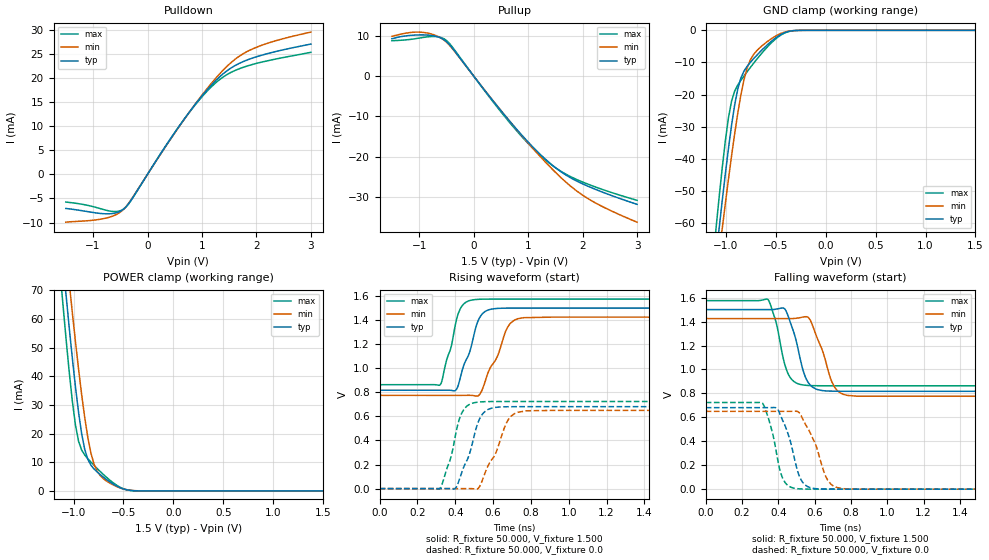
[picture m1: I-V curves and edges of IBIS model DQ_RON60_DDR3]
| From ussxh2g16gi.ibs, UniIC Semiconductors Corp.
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|   Model DQ_RON60_DDR3
[Model] DQ_RON60_DDR3
Model_type I/O
Vinl =  0.615V
Vinh =  0.885V
Vmeas =  0.750V
Rref =  50.000
Vref =  0.750V
C_comp   0.966pF   0.965pF   0.967pF
[Model Spec]
Vinh   0.885V   0.847V   0.922V
Vinl   0.615V   0.577V   0.652V
Vmeas   0.750V   0.712V   0.787V
Vref   0.750V   0.712V   0.787V
Rref   50.000   NA   NA
[Temperature Range]   25.000   95.000   -40.000
[Voltage Range]   1.500V   1.425V   1.575V
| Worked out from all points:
|   slope of the pulldown table from 0 to 0.225 V, typ, clamps not added: 56.5 ohm
|   slope of the pullup table from 0 to 0.225 V, typ, clamps not added: 57.4 ohm
|   GND clamp passes 1 mA (typ) near -0.43 V on its own axis
|   POWER clamp passes 1 mA (typ) near -0.52 V on its own axis
|   rising waveform, R_fixture 50.000, V_fixture 1.500: 20-80 % time 81.6ps typ, 103ps min, 66.8ps max; typ from 0.818 V to 1.5 V
|   rising waveform, R_fixture 50.000, V_fixture 0.0: 20-80 % time 84.5ps typ, 106ps min, 70.8ps max; typ from 0 V to 0.681 V
|   falling waveform, R_fixture 50.000, V_fixture 1.500: 20-80 % time 72ps typ, 86.9ps min, 63.1ps max; typ from 1.5 V to 0.818 V
|   falling waveform, R_fixture 50.000, V_fixture 0.0: 20-80 % time 76.5ps typ, 97.3ps min, 63.5ps max; typ from 0.681 V to 0 V
[Pulldown]
|Voltage   I(typ)   I(min)   I(max)
-1.5V     -7.077mA   -9.924mA   -5.748mA
-764mV    -8.187mA   -9.081mA   -7.434mA
-580mV    -7.998mA   -8.377mA   -7.72mA
-442mV    -7.252mA   -7.298mA   -7.217mA
-304mV    -5.41mA    -5.318mA   -5.451mA
662mV     11.26mA    11.21mA    11.24mA
984mV     16.05mA    16.18mA    15.87mA
1.26V     19.52mA    20.01mA    19.05mA
1.582V    22.39mA    23.63mA    21.41mA
1.858V    23.83mA    25.63mA    22.55mA
2.318V    25.36mA    27.58mA    23.82mA
3V        27.01mA    29.49mA    25.3mA
[Pullup]
|Voltage   I(typ)   I(min)   I(max)
-1.5V     9.205mA    9.811mA    8.722mA
-956mV    10.16mA    10.81mA    9.463mA
-726mV    9.917mA    10.17mA    9.772mA
-542mV    8.946mA    8.844mA    9.189mA
-404mV    7.122mA    6.979mA    7.402mA
700mV     -11.77mA   -11.79mA   -12.12mA
1.022V    -16.63mA   -16.89mA   -16.98mA
1.344V    -20.88mA   -21.65mA   -21.06mA
1.666V    -24.23mA   -25.9mA    -24.06mA
2.034V    -26.86mA   -29.75mA   -26.39mA
2.402V    -28.9mA    -32.53mA   -28.22mA
3V        -31.73mA   -36.14mA   -30.74mA
[GND_clamp]
|Voltage   I(typ)   I(min)   I(max)
-1.5V     -194.2mA   -188.5mA   -200.2mA
-1.097V   -70.36mA   -77.53mA   -61.46mA
-1.066V   -61.52mA   -69.48mA   -51.83mA
-1.035V   -52.91mA   -61.57mA   -42.69mA
-973mV    -36.75mA   -46.31mA   -27.23mA
-942mV    -29.54mA   -39.07mA   -22.03mA
-880mV    -18.29mA   -25.85mA   -17.02mA
-787mV    -11.24mA   -11.84mA   -12.91mA
-694mV    -7.909mA   -6.483mA   -9.178mA
-539mV    -3.3mA     -2.519mA   -3.76mA
-291mV    -42.28uA   -42.7uA    -38.22uA
1.5V      0A         0A         0A
[POWER_clamp]
|Voltage   I(typ)   I(min)   I(max)
-1.5V     238.9mA    243.4mA    236.4mA
-1.135V   91.01mA    105.1mA    76.96mA
-1.104V   79.29mA    94.04mA    64.51mA
-1.073V   67.84mA    83.12mA    52.53mA
-1.042V   56.75mA    72.44mA    41.28mA
-1.011V   46.15mA    62.05mA    31.18mA
-980mV    36.24mA    52.02mA    22.93mA
-887mV    14.41mA    25.48mA    12.52mA
-794mV    7.645mA    9.305mA    8.93mA
-670mV    3.99mA     3.471mA    4.77mA
-391mV    72.25uA    105.7uA    45.94uA
1.5V      0A         0A         0A
[Ramp]
| variable   typ   min   max
dV/dt_r   0.409/84.474p   0.390/0.106n   0.434/70.864p
dV/dt_f   0.409/71.683p   0.390/86.888p   0.427/62.993p
R_load = 50.000
[Rising Waveform]
R_fixture= 50.000
V_fixture= 1.500
V_fixture_min= 1.425
V_fixture_max= 1.575
|time   V(typ)   V(min)   V(max)
0s        817.6mV    774.9mV    863.6mV
318ps     817.5mV    774.9mV    859.9mV
405ps     821.8mV    774.9mV    1.396V
437ps     985.2mV    774.9mV    1.521V
493ps     1.239V     773.8mV    1.568V
520ps     1.392V     770.1mV    1.573V
558ps     1.472V     891.4mV    1.574V
677ps     1.5V       1.342V     1.575V
761ps     1.5V       1.42V      1.575V
3ns       1.5V       1.425V     1.575V
[Rising Waveform]
R_fixture= 50.000
V_fixture= 0.0
V_fixture_min= 0.0
V_fixture_max= 0.0
|time   V(typ)   V(min)   V(max)
0s        223nV      1.468uV    104.7nV
318ps     -36.75uV   3.619uV    -722.7uV
378ps     -789.6uV   2.971uV    268.1mV
405ps     11.05mV    -13.46uV   476mV
442ps     168.5mV    21.03uV    649.6mV
511ps     505.3mV    -4.537mV   716.9mV
571ps     655.8mV    182.9mV    723mV
671ps     680.2mV    547.7mV    723.8mV
729ps     680.9mV    634mV      723.8mV
3ns       681.1mV    650.1mV    723.8mV
[Falling Waveform]
R_fixture= 50.000
V_fixture= 1.500
V_fixture_min= 1.425
V_fixture_max= 1.575
|time   V(typ)   V(min)   V(max)
0s        1.5V       1.425V     1.575V
342ps     1.5V       1.425V     1.584V
386ps     1.503V     1.425V     1.403V
443ps     1.487V     1.425V     1.004V
497ps     1.248V     1.427V     888.3mV
532ps     1.014V     1.437V     871.3mV
576ps     868.3mV    1.412V     865.4mV
710ps     818.2mV    852mV      863.6mV
782ps     817.6mV    783.2mV    863.6mV
3ns       817.6mV    774.9mV    863.6mV
[Falling Waveform]
R_fixture= 50.000
V_fixture= 0.0
V_fixture_min= 0.0
V_fixture_max= 0.0
|time   V(typ)   V(min)   V(max)
0s        681.1mV    650.1mV    723.8mV
313ps     681mV      650mV      717.6mV
366ps     681.5mV    650mV      479.3mV
399ps     660.4mV    650mV      223.9mV
437ps     530.2mV    650mV      55.66mV
492ps     232.8mV    651.1mV    6.928mV
557ps     25.04mV    522mV      592.7uV
671ps     405.4uV    77.49mV    7.127uV
741ps     30.4uV     7.48mV     680.3nV
3ns       258.2nV    1.483uV    185.5nV
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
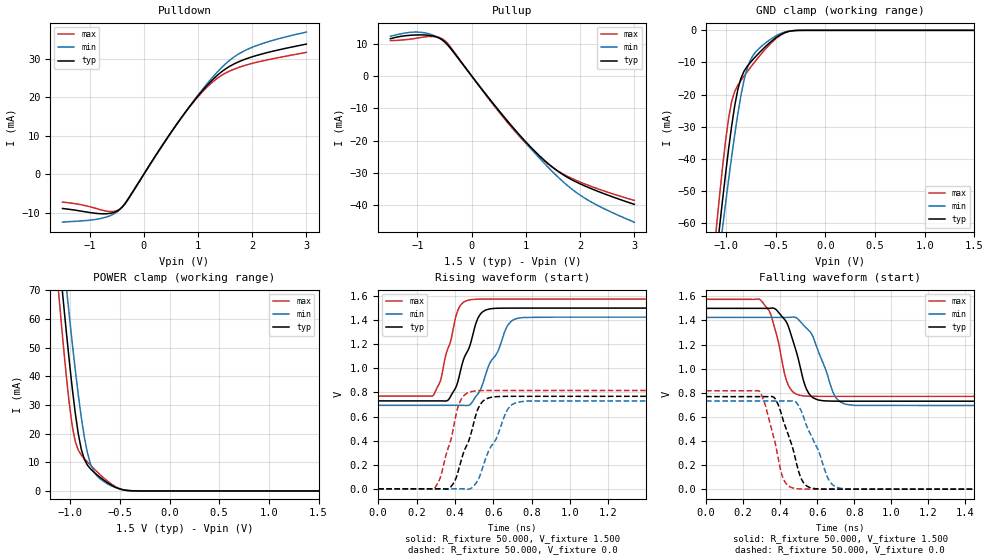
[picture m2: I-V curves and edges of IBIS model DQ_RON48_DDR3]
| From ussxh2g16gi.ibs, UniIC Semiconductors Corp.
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|   Model DQ_RON48_DDR3
[Model] DQ_RON48_DDR3
Model_type I/O
Vinl =  0.615V
Vinh =  0.885V
Vmeas =  0.750V
Rref =  50.000
Vref =  0.750V
C_comp   0.966pF   0.965pF   0.967pF
[Model Spec]
Vinh   0.885V   0.847V   0.922V
Vinl   0.615V   0.577V   0.652V
Vmeas   0.750V   0.712V   0.787V
Vref   0.750V   0.712V   0.787V
Rref   50.000   NA   NA
[Temperature Range]   25.000   95.000   -40.000
[Voltage Range]   1.500V   1.425V   1.575V
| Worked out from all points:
|   slope of the pulldown table from 0 to 0.225 V, typ, clamps not added: 45.2 ohm
|   slope of the pullup table from 0 to 0.225 V, typ, clamps not added: 45.9 ohm
|   GND clamp passes 1 mA (typ) near -0.43 V on its own axis
|   POWER clamp passes 1 mA (typ) near -0.52 V on its own axis
|   rising waveform, R_fixture 50.000, V_fixture 1.500: 20-80 % time 90.1ps typ, 117ps min, 72.2ps max; typ from 0.73 V to 1.5 V
|   rising waveform, R_fixture 50.000, V_fixture 0.0: 20-80 % time 91.1ps typ, 115ps min, 75.6ps max; typ from 0 V to 0.768 V
|   falling waveform, R_fixture 50.000, V_fixture 1.500: 20-80 % time 84.2ps typ, 104ps min, 72.3ps max; typ from 1.5 V to 0.73 V
|   falling waveform, R_fixture 50.000, V_fixture 0.0: 20-80 % time 90.3ps typ, 114ps min, 74.6ps max; typ from 0.768 V to 0 V
[Pulldown]
|Voltage   I(typ)   I(min)   I(max)
-1.5V     -8.855mA   -12.42mA   -7.198mA
-764mV    -10.24mA   -11.36mA   -9.305mA
-580mV    -10mA      -10.48mA   -9.66mA
-442mV    -9.069mA   -9.126mA   -9.029mA
-304mV    -6.766mA   -6.65mA    -6.819mA
662mV     14.08mA    14.02mA    14.06mA
984mV     20.07mA    20.24mA    19.85mA
1.26V     24.41mA    25.03mA    23.83mA
1.582V    28.01mA    29.56mA    26.79mA
1.858V    29.82mA    32.07mA    28.23mA
2.318V    31.73mA    34.51mA    29.82mA
3V        33.8mA     36.92mA    31.67mA
[Pullup]
|Voltage   I(typ)   I(min)   I(max)
-1.5V     11.52mA    12.28mA    10.93mA
-956mV    12.71mA    13.53mA    11.85mA
-726mV    12.41mA    12.72mA    12.23mA
-542mV    11.19mA    11.06mA    11.5mA
-404mV    8.909mA    8.73mA     9.263mA
700mV     -14.73mA   -14.75mA   -15.17mA
1.022V    -20.8mA    -21.12mA   -21.25mA
1.344V    -26.12mA   -27.08mA   -26.36mA
1.666V    -30.31mA   -32.4mA    -30.11mA
2.034V    -33.61mA   -37.23mA   -33.05mA
2.402V    -36.16mA   -40.71mA   -35.34mA
3V        -39.7mA    -45.23mA   -38.49mA
[GND_clamp]
|Voltage   I(typ)   I(min)   I(max)
-1.5V     -194.2mA   -188.5mA   -200.2mA
-1.097V   -70.36mA   -77.53mA   -61.46mA
-1.066V   -61.52mA   -69.48mA   -51.83mA
-1.035V   -52.91mA   -61.57mA   -42.69mA
-973mV    -36.75mA   -46.31mA   -27.23mA
-942mV    -29.54mA   -39.07mA   -22.03mA
-880mV    -18.29mA   -25.85mA   -17.02mA
-787mV    -11.24mA   -11.84mA   -12.91mA
-694mV    -7.909mA   -6.483mA   -9.178mA
-539mV    -3.3mA     -2.519mA   -3.76mA
-291mV    -42.28uA   -42.7uA    -38.22uA
1.5V      0A         0A         0A
[POWER_clamp]
|Voltage   I(typ)   I(min)   I(max)
-1.5V     238.9mA    243.4mA    236.4mA
-1.135V   91.01mA    105.1mA    76.96mA
-1.104V   79.29mA    94.04mA    64.51mA
-1.073V   67.84mA    83.12mA    52.53mA
-1.042V   56.75mA    72.44mA    41.28mA
-1.011V   46.15mA    62.05mA    31.18mA
-980mV    36.24mA    52.02mA    22.93mA
-887mV    14.41mA    25.48mA    12.52mA
-794mV    7.645mA    9.305mA    8.93mA
-670mV    3.99mA     3.471mA    4.77mA
-391mV    72.25uA    105.7uA    45.94uA
1.5V      0A         0A         0A
[Ramp]
| variable   typ   min   max
dV/dt_r   0.461/90.981p   0.439/0.115n   0.490/75.637p
dV/dt_f   0.462/83.868p   0.439/0.104n   0.483/72.416p
R_load = 50.000
[Rising Waveform]
R_fixture= 50.000
V_fixture= 1.500
V_fixture_min= 1.425
V_fixture_max= 1.575
|time   V(typ)   V(min)   V(max)
0s        729.8mV    693mV      769.8mV
290ps     729.8mV    693mV      781.2mV
324ps     729.8mV    693mV      894.4mV
370ps     747.4mV    693mV      1.189V
416ps     894.5mV    693.1mV    1.485V
478ps     1.189V     697.6mV    1.569V
542ps     1.466V     859.3mV    1.575V
669ps     1.5V       1.34V      1.575V
727ps     1.5V       1.416V     1.575V
3ns       1.5V       1.425V     1.575V
[Rising Waveform]
R_fixture= 50.000
V_fixture= 0.0
V_fixture_min= 0.0
V_fixture_max= 0.0
|time   V(typ)   V(min)   V(max)
0s        208.5nV    1.321uV    107.7nV
296ps     -18.19uV   4.319uV    9.245mV
328ps     122.6uV    5.59uV     115.8mV
398ps     60.93mV    18.37uV    556.4mV
436ps     255.5mV    130.7uV    752mV
493ps     515.5mV    15.18mV    809.4mV
552ps     735.6mV    213.1mV    815.8mV
673ps     767.5mV    654.6mV    816.5mV
722ps     767.9mV    718.1mV    816.5mV
3ns       767.9mV    731.2mV    816.5mV
[Falling Waveform]
R_fixture= 50.000
V_fixture= 1.500
V_fixture_min= 1.425
V_fixture_max= 1.575
|time   V(typ)   V(min)   V(max)
0s        1.5V       1.425V     1.575V
295ps     1.5V       1.425V     1.568V
352ps     1.502V     1.425V     1.435V
434ps     1.385V     1.425V     900.6mV
507ps     1.02V      1.394V     778.6mV
543ps     825.2mV    1.334V     772.1mV
575ps     760.7mV    1.271V     770.5mV
684ps     730.4mV    807.6mV    769.8mV
754ps     729.9mV    703.6mV    769.8mV
3ns       729.8mV    693mV      769.8mV
[Falling Waveform]
R_fixture= 50.000
V_fixture= 0.0
V_fixture_min= 0.0
V_fixture_max= 0.0
|time   V(typ)   V(min)   V(max)
0s        767.9mV    731.2mV    816.5mV
288ps     767.9mV    731.2mV    812.1mV
372ps     751.8mV    731.2mV    388.2mV
415ps     577.3mV    731.1mV    93.48mV
479ps     271.5mV    728.9mV    6.137mV
513ps     88.14mV    650.3mV    1.422mV
546ps     23.8mV     511.8mV    343.3uV
666ps     177.5uV    66.82mV    1.999uV
732ps     11.67uV    5.786mV    401.4nV
3ns       217.6nV    1.311uV    247.7nV
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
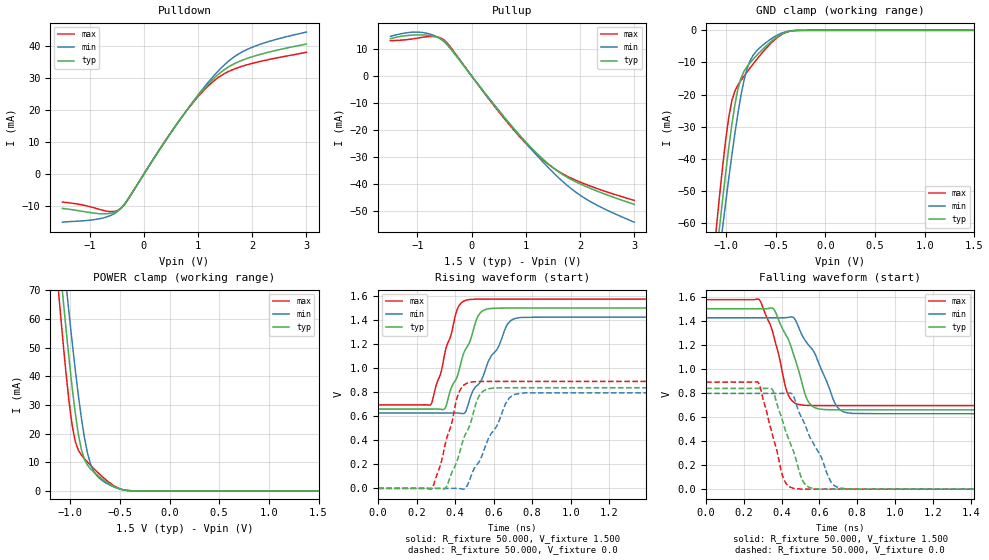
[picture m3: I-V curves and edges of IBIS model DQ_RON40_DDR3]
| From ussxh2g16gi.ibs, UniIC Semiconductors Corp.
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|   Model DQ_RON40_DDR3
[Model] DQ_RON40_DDR3
Model_type I/O
Vinl =  0.615V
Vinh =  0.885V
Vmeas =  0.750V
Rref =  50.000
Vref =  0.750V
C_comp   0.966pF   0.965pF   0.967pF
[Model Spec]
Vinh   0.885V   0.847V   0.922V
Vinl   0.615V   0.577V   0.652V
Vmeas   0.750V   0.712V   0.787V
Vref   0.750V   0.712V   0.787V
Rref   50.000   NA   NA
[Temperature Range]   25.000   95.000   -40.000
[Voltage Range]   1.500V   1.425V   1.575V
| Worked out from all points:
|   slope of the pulldown table from 0 to 0.225 V, typ, clamps not added: 37.7 ohm
|   slope of the pullup table from 0 to 0.225 V, typ, clamps not added: 38.3 ohm
|   GND clamp passes 1 mA (typ) near -0.43 V on its own axis
|   POWER clamp passes 1 mA (typ) near -0.52 V on its own axis
|   rising waveform, R_fixture 50.000, V_fixture 1.500: 20-80 % time 119ps typ, 160ps min, 91.2ps max; typ from 0.659 V to 1.5 V
|   rising waveform, R_fixture 50.000, V_fixture 0.0: 20-80 % time 108ps typ, 148ps min, 83.2ps max; typ from 0 V to 0.837 V
|   falling waveform, R_fixture 50.000, V_fixture 1.500: 20-80 % time 112ps typ, 151ps min, 87.1ps max; typ from 1.5 V to 0.659 V
|   falling waveform, R_fixture 50.000, V_fixture 0.0: 20-80 % time 107ps typ, 141ps min, 85.9ps max; typ from 0.837 V to 0 V
[Pulldown]
|Voltage   I(typ)   I(min)   I(max)
-1.5V     -10.61mA   -14.88mA   -8.617mA
-764mV    -12.27mA   -13.61mA   -11.14mA
-580mV    -11.99mA   -12.56mA   -11.57mA
-442mV    -10.87mA   -10.94mA   -10.82mA
-304mV    -8.107mA   -7.968mA   -8.167mA
662mV     16.87mA    16.8mA     16.84mA
984mV     24.04mA    24.25mA    23.77mA
1.26V     29.25mA    29.99mA    28.54mA
1.582V    33.55mA    35.4mA     32.08mA
1.858V    35.71mA    38.4mA     33.8mA
2.318V    38.01mA    41.32mA    35.7mA
3V        40.48mA    44.19mA    37.92mA
[Pullup]
|Voltage   I(typ)   I(min)   I(max)
-1.5V     13.8mA     14.7mA     13.07mA
-956mV    15.23mA    16.21mA    14.19mA
-726mV    14.86mA    15.24mA    14.65mA
-542mV    13.41mA    13.25mA    13.77mA
-404mV    10.67mA    10.46mA    11.09mA
700mV     -17.64mA   -17.67mA   -18.15mA
1.022V    -24.91mA   -25.3mA    -25.43mA
1.344V    -31.28mA   -32.43mA   -31.54mA
1.666V    -36.29mA   -38.79mA   -36.03mA
2.034V    -40.23mA   -44.56mA   -39.53mA
2.402V    -43.28mA   -48.71mA   -42.27mA
3V        -47.51mA   -54.1mA    -46.03mA
[GND_clamp]
|Voltage   I(typ)   I(min)   I(max)
-1.5V     -194.2mA   -188.5mA   -200.2mA
-1.097V   -70.36mA   -77.53mA   -61.46mA
-1.066V   -61.52mA   -69.48mA   -51.83mA
-1.035V   -52.91mA   -61.57mA   -42.69mA
-973mV    -36.75mA   -46.31mA   -27.23mA
-942mV    -29.54mA   -39.07mA   -22.03mA
-880mV    -18.29mA   -25.85mA   -17.02mA
-787mV    -11.24mA   -11.84mA   -12.91mA
-694mV    -7.909mA   -6.483mA   -9.178mA
-539mV    -3.3mA     -2.519mA   -3.76mA
-291mV    -42.28uA   -42.7uA    -38.22uA
1.5V      0A         0A         0A
[POWER_clamp]
|Voltage   I(typ)   I(min)   I(max)
-1.5V     238.9mA    243.4mA    236.4mA
-1.135V   91.01mA    105.1mA    76.96mA
-1.104V   79.29mA    94.04mA    64.51mA
-1.073V   67.84mA    83.12mA    52.53mA
-1.042V   56.75mA    72.44mA    41.28mA
-1.011V   46.15mA    62.05mA    31.18mA
-980mV    36.24mA    52.02mA    22.93mA
-887mV    14.41mA    25.48mA    12.52mA
-794mV    7.645mA    9.305mA    8.93mA
-670mV    3.99mA     3.471mA    4.77mA
-391mV    72.25uA    105.7uA    45.94uA
1.5V      0A         0A         0A
[Ramp]
| variable   typ   min   max
dV/dt_r   0.502/0.108n   0.478/0.148n   0.534/83.194p
dV/dt_f   0.504/0.112n   0.479/0.151n   0.528/86.940p
R_load = 50.000
[Rising Waveform]
R_fixture= 50.000
V_fixture= 1.500
V_fixture_min= 1.425
V_fixture_max= 1.575
|time   V(typ)   V(min)   V(max)
0s        659.5mV    627.1mV    694.9mV
276ps     659.4mV    627.1mV    702.7mV
349ps     671.3mV    627.1mV    1.144V
415ps     951.4mV    626.9mV    1.504V
451ps     1.149V     629.5mV    1.562V
468ps     1.192V     698.3mV    1.569V
538ps     1.472V     905.8mV    1.575V
666ps     1.5V       1.349V     1.575V
716ps     1.5V       1.416V     1.575V
3ns       1.5V       1.425V     1.575V
[Rising Waveform]
R_fixture= 50.000
V_fixture= 0.0
V_fixture_min= 0.0
V_fixture_max= 0.0
|time   V(typ)   V(min)   V(max)
0s        197.4nV    1.203uV    110.9nV
278ps     -66.61uV   3.295uV    -1.742mV
353ps     9.699mV    -49.68uV   398.3mV
422ps     291.8mV    -941.6uV   807.3mV
477ps     529.5mV    78.62mV    882mV
516ps     741.7mV    202.7mV    888.3mV
543ps     805.1mV    287.8mV    889.4mV
669ps     837.3mV    725.3mV    889.9mV
712ps     837.4mV    783.4mV    889.9mV
3ns       837.4mV    796.3mV    889.9mV
[Falling Waveform]
R_fixture= 50.000
V_fixture= 1.500
V_fixture_min= 1.425
V_fixture_max= 1.575
|time   V(typ)   V(min)   V(max)
0s        1.5V       1.425V     1.575V
281ps     1.5V       1.425V     1.576V
363ps     1.485V     1.425V     1.242V
430ps     1.262V     1.427V     801.3mV
466ps     1.105V     1.421V     719.9mV
499ps     934.8mV    1.31V      701.3mV
561ps     691mV      1.165V     695.4mV
679ps     659.7mV    722.9mV    694.9mV
746ps     659.5mV    635.2mV    694.9mV
3ns       659.5mV    627.1mV    694.9mV
[Falling Waveform]
R_fixture= 50.000
V_fixture= 0.0
V_fixture_min= 0.0
V_fixture_max= 0.0
|time   V(typ)   V(min)   V(max)
0s        837.4mV    796.3mV    889.9mV
274ps     837.4mV    796.3mV    890mV
352ps     823.8mV    796.3mV    445.5mV
414ps     518mV      796.2mV    72.23mV
467ps     295mV      757.2mV    5.888mV
500ps     112.7mV    610.4mV    1.231mV
532ps     28.36mV    500.3mV    280.8uV
662ps     87.94uV    58.13mV    776.6nV
701ps     15.26uV    12.07mV    330.4nV
3ns       226.3nV    1.164uV    156.2nV
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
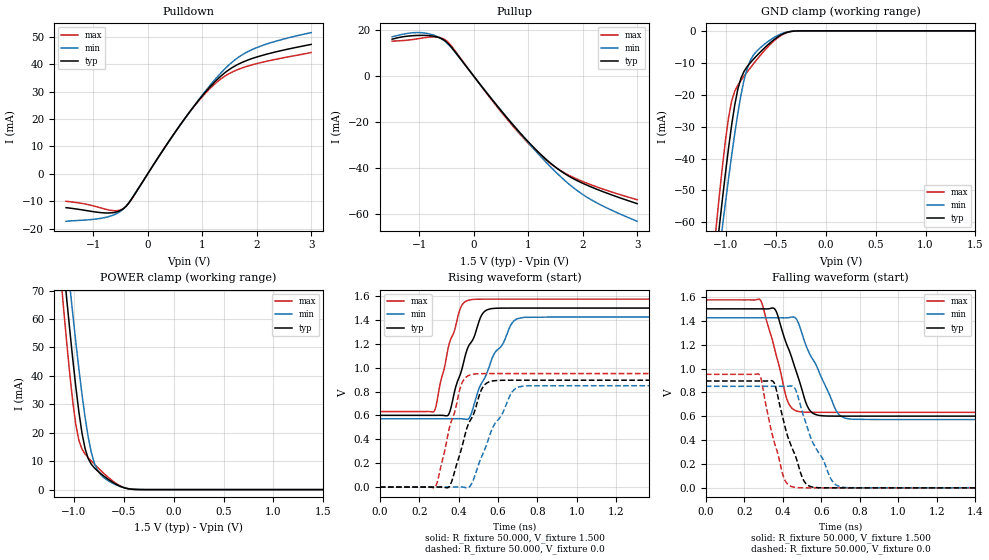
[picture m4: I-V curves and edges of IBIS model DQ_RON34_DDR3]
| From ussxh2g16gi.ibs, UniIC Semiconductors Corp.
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|   Model DQ_RON34_DDR3
[Model] DQ_RON34_DDR3
Model_type I/O
Vinl =  0.615V
Vinh =  0.885V
Vmeas =  0.750V
Rref =  50.000
Vref =  0.750V
C_comp   0.966pF   0.965pF   0.967pF
[Model Spec]
Vinh   0.885V   0.847V   0.922V
Vinl   0.615V   0.577V   0.652V
Vmeas   0.750V   0.712V   0.787V
Vref   0.750V   0.712V   0.787V
Rref   50.000   NA   NA
[Temperature Range]   25.000   95.000   -40.000
[Voltage Range]   1.500V   1.425V   1.575V
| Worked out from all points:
|   slope of the pulldown table from 0 to 0.225 V, typ, clamps not added: 32.3 ohm
|   slope of the pullup table from 0 to 0.225 V, typ, clamps not added: 32.8 ohm
|   GND clamp passes 1 mA (typ) near -0.43 V on its own axis
|   POWER clamp passes 1 mA (typ) near -0.52 V on its own axis
|   rising waveform, R_fixture 50.000, V_fixture 1.500: 20-80 % time 114ps typ, 151ps min, 89.1ps max; typ from 0.601 V to 1.5 V
|   rising waveform, R_fixture 50.000, V_fixture 0.0: 20-80 % time 108ps typ, 142ps min, 85.1ps max; typ from 0 V to 0.896 V
|   falling waveform, R_fixture 50.000, V_fixture 1.500: 20-80 % time 111ps typ, 145ps min, 90.4ps max; typ from 1.5 V to 0.601 V
|   falling waveform, R_fixture 50.000, V_fixture 0.0: 20-80 % time 102ps typ, 132ps min, 83.7ps max; typ from 0.896 V to 0 V
[Pulldown]
|Voltage   I(typ)   I(min)   I(max)
-1.5V     -12.39mA   -17.36mA   -10.06mA
-764mV    -14.32mA   -15.88mA   -13.01mA
-580mV    -13.99mA   -14.65mA   -13.51mA
-442mV    -12.68mA   -12.76mA   -12.62mA
-304mV    -9.452mA   -9.291mA   -9.524mA
662mV     19.67mA    19.59mA    19.64mA
984mV     28.04mA    28.27mA    27.73mA
1.26V     34.11mA    34.97mA    33.29mA
1.582V    39.13mA    41.28mA    37.42mA
1.858V    41.65mA    44.78mA    39.43mA
2.318V    44.33mA    48.19mA    41.64mA
3V        47.22mA    51.54mA    44.24mA
[Pullup]
|Voltage   I(typ)   I(min)   I(max)
-1.5V     16.11mA    17.15mA    15.27mA
-956mV    17.77mA    18.93mA    16.57mA
-726mV    17.35mA    17.79mA    17.1mA
-542mV    15.64mA    15.46mA    16.07mA
-404mV    12.45mA    12.2mA     12.94mA
700mV     -20.57mA   -20.61mA   -21.19mA
1.022V    -29.06mA   -29.51mA   -29.68mA
1.344V    -36.49mA   -37.83mA   -36.81mA
1.666V    -42.33mA   -45.25mA   -42.06mA
2.034V    -46.94mA   -51.98mA   -46.14mA
2.402V    -50.49mA   -56.83mA   -49.34mA
3V        -55.43mA   -63.11mA   -53.74mA
[GND_clamp]
|Voltage   I(typ)   I(min)   I(max)
-1.5V     -194.2mA   -188.5mA   -200.2mA
-1.097V   -70.36mA   -77.53mA   -61.46mA
-1.066V   -61.52mA   -69.48mA   -51.83mA
-1.035V   -52.91mA   -61.57mA   -42.69mA
-973mV    -36.75mA   -46.31mA   -27.23mA
-942mV    -29.54mA   -39.07mA   -22.03mA
-880mV    -18.29mA   -25.85mA   -17.02mA
-787mV    -11.24mA   -11.84mA   -12.91mA
-694mV    -7.909mA   -6.483mA   -9.178mA
-539mV    -3.3mA     -2.519mA   -3.76mA
-291mV    -42.28uA   -42.7uA    -38.22uA
1.5V      0A         0A         0A
[POWER_clamp]
|Voltage   I(typ)   I(min)   I(max)
-1.5V     238.9mA    243.4mA    236.4mA
-1.135V   91.01mA    105.1mA    76.96mA
-1.104V   79.29mA    94.04mA    64.51mA
-1.073V   67.84mA    83.12mA    52.53mA
-1.042V   56.75mA    72.44mA    41.28mA
-1.011V   46.15mA    62.05mA    31.18mA
-980mV    36.24mA    52.02mA    22.93mA
-887mV    14.41mA    25.48mA    12.52mA
-794mV    7.645mA    9.305mA    8.93mA
-670mV    3.99mA     3.471mA    4.77mA
-391mV    72.25uA    105.7uA    45.94uA
1.5V      0A         0A         0A
[Ramp]
| variable   typ   min   max
dV/dt_r   0.537/0.108n   0.510/0.142n   0.571/85.190p
dV/dt_f   0.539/0.111n   0.512/0.145n   0.565/90.271p
R_load = 50.000
[Rising Waveform]
R_fixture= 50.000
V_fixture= 1.500
V_fixture_min= 1.425
V_fixture_max= 1.575
|time   V(typ)   V(min)   V(max)
0s        601.1mV    572.4mV    632.7mV
276ps     601mV      572.5mV    635.5mV
352ps     617.7mV    572.4mV    1.201V
411ps     957.8mV    572.7mV    1.507V
455ps     1.195V     580mV      1.568V
535ps     1.476V     923.5mV    1.575V
573ps     1.496V     1.093V     1.575V
672ps     1.5V       1.378V     1.575V
731ps     1.5V       1.422V     1.575V
3ns       1.5V       1.425V     1.575V
[Rising Waveform]
R_fixture= 50.000
V_fixture= 0.0
V_fixture_min= 0.0
V_fixture_max= 0.0
|time   V(typ)   V(min)   V(max)
0s        187.9nV    1.105uV    113.1nV
281ps     -80.66uV   3.744uV    278uV
359ps     23.7mV     -66.36uV   534.3mV
416ps     332.9mV    210uV      868.9mV
473ps     601mV      54.4mV     945.8mV
536ps     863.6mV    330.4mV    951.1mV
572ps     889.3mV    497.5mV    951.3mV
667ps     895.5mV    787.1mV    951.4mV
719ps     895.6mV    844.2mV    951.4mV
3ns       895.6mV    850.7mV    951.4mV
[Falling Waveform]
R_fixture= 50.000
V_fixture= 1.500
V_fixture_min= 1.425
V_fixture_max= 1.575
|time   V(typ)   V(min)   V(max)
0s        1.5V       1.425V     1.575V
283ps     1.5V       1.425V     1.575V
365ps     1.482V     1.425V     1.117V
424ps     1.187V     1.425V     730.9mV
482ps     916.2mV    1.379V     639.9mV
526ps     690mV      1.172V     633.7mV
552ps     630.6mV    1.087V     633mV
678ps     601.2mV    645.3mV    632.7mV
741ps     601.1mV    578.3mV    632.7mV
3ns       601.1mV    572.4mV    632.7mV
[Falling Waveform]
R_fixture= 50.000
V_fixture= 0.0
V_fixture_min= 0.0
V_fixture_max= 0.0
|time   V(typ)   V(min)   V(max)
0s        895.6mV    850.7mV    951.4mV
280ps     895.5mV    850.7mV    945.4mV
357ps     873.1mV    850.7mV    375.7mV
409ps     529.1mV    850.4mV    71.39mV
457ps     301.7mV    847.9mV    6.079mV
501ps     87.93mV    639mV      607.7uV
530ps     22.28mV    493.9mV    131.1uV
654ps     57.75uV    63.91mV    525.9nV
697ps     7.75uV     9.89mV     286.6nV
3ns       165.2nV    1.074uV    89.97nV
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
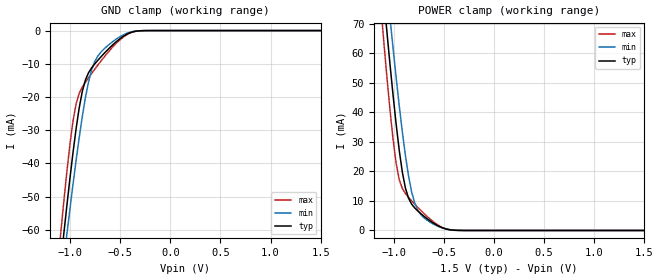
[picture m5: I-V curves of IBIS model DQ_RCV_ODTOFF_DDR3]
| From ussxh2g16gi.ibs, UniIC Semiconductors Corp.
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|   Model DQ_RCV_ODTOFF_DDR3
[Model] DQ_RCV_ODTOFF_DDR3
Model_type Input
Vinl =  0.615V
Vinh =  0.885V
C_comp   0.966pF   0.965pF   0.967pF
[Model Spec]
Vinh   0.885V   0.847V   0.922V
Vinl   0.615V   0.577V   0.652V
[Temperature Range]   25.000   95.000   -40.000
[Voltage Range]   1.500V   1.425V   1.575V
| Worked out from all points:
|   GND clamp passes 1 mA (typ) near -0.43 V on its own axis
|   POWER clamp passes 1 mA (typ) near -0.52 V on its own axis
[GND_clamp]
|Voltage   I(typ)   I(min)   I(max)
-1.5V     -194.2mA   -188.5mA   -200.2mA
-1.097V   -70.36mA   -77.53mA   -61.46mA
-1.066V   -61.52mA   -69.48mA   -51.83mA
-1.035V   -52.91mA   -61.57mA   -42.69mA
-973mV    -36.75mA   -46.31mA   -27.23mA
-942mV    -29.54mA   -39.07mA   -22.03mA
-880mV    -18.29mA   -25.85mA   -17.02mA
-787mV    -11.24mA   -11.84mA   -12.91mA
-694mV    -7.909mA   -6.483mA   -9.178mA
-539mV    -3.3mA     -2.519mA   -3.76mA
-291mV    -42.28uA   -42.7uA    -38.22uA
1.5V      0A         0A         0A
[POWER_clamp]
|Voltage   I(typ)   I(min)   I(max)
-1.5V     238.9mA    243.4mA    236.4mA
-1.135V   91.01mA    105.1mA    76.96mA
-1.104V   79.29mA    94.04mA    64.51mA
-1.073V   67.84mA    83.12mA    52.53mA
-1.042V   56.75mA    72.44mA    41.28mA
-1.011V   46.15mA    62.05mA    31.18mA
-980mV    36.24mA    52.02mA    22.93mA
-887mV    14.41mA    25.48mA    12.52mA
-794mV    7.645mA    9.305mA    8.93mA
-670mV    3.99mA     3.471mA    4.77mA
-391mV    72.25uA    105.7uA    45.94uA
1.5V      0A         0A         0A
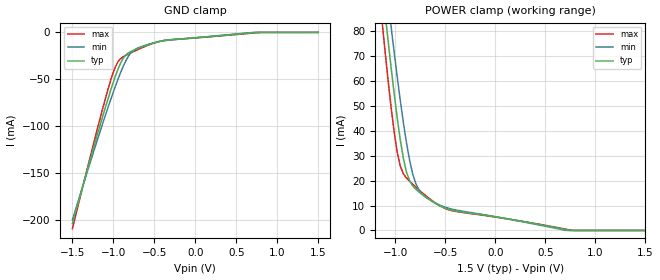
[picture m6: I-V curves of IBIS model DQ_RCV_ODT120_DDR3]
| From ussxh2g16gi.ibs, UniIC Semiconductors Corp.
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|   Model DQ_RCV_ODT120_DDR3
[Model] DQ_RCV_ODT120_DDR3
Model_type Input
Vinl =  0.615V
Vinh =  0.885V
C_comp   0.966pF   0.965pF   0.967pF
[Model Spec]
Vinh   0.885V   0.847V   0.922V
Vinl   0.615V   0.577V   0.652V
[Temperature Range]   25.000   95.000   -40.000
[Voltage Range]   1.500V   1.425V   1.575V
[GND_clamp]
|Voltage   I(typ)   I(min)   I(max)
-1.5V     -204mA     -200mA     -209.5mA
-1.252V   -126.2mA   -130.3mA   -122.2mA
-1.066V   -70.97mA   -80.25mA   -60.88mA
-973mV    -46.13mA   -56.89mA   -36.24mA
-911mV    -32.58mA   -42.66mA   -27.9mA
-849mV    -24.13mA   -30.5mA    -24.53mA
-818mV    -21.94mA   -25.7mA    -23.17mA
-756mV    -19.19mA   -19.43mA   -20.57mA
-663mV    -15.91mA   -15.34mA   -16.87mA
-446mV    -9.729mA   -9.883mA   -9.903mA
701mV     -368.9uA   -91.38uA   -759.9uA
1.5V      0A         0A         0A
[POWER_clamp]
|Voltage   I(typ)   I(min)   I(max)
-1.5V     248mA      253.3mA    245.1mA
-1.135V   100.1mA    115mA      85.49mA
-1.104V   88.4mA     103.9mA    73.03mA
-1.073V   76.94mA    92.95mA    61.05mA
-1.042V   65.83mA    82.25mA    49.8mA
-980mV    45.29mA    61.77mA    31.45mA
-887mV    23.4mA     35.12mA    21.04mA
-794mV    16.54mA    18.8mA     17.43mA
-670mV    12.71mA    12.7mA     13.18mA
-422mV    8.08mA     8.46mA     7.859mA
694mV     446.4uA    150.6uA    608.5uA
1.5V      0A         0A         0A
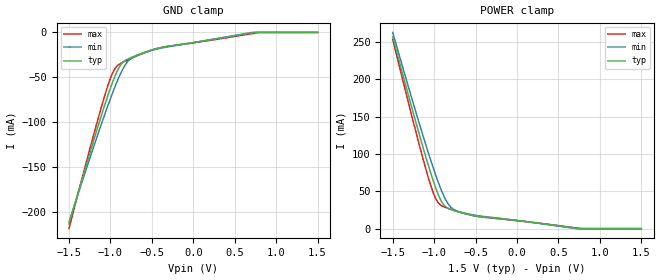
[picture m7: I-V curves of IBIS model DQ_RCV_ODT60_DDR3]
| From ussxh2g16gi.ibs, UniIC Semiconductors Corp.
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|   Model DQ_RCV_ODT60_DDR3
[Model] DQ_RCV_ODT60_DDR3
Model_type Input
Vinl =  0.615V
Vinh =  0.885V
C_comp   0.966pF   0.965pF   0.967pF
[Model Spec]
Vinh   0.885V   0.847V   0.922V
Vinl   0.615V   0.577V   0.652V
[Temperature Range]   25.000   95.000   -40.000
[Voltage Range]   1.500V   1.425V   1.575V
[GND_clamp]
|Voltage   I(typ)   I(min)   I(max)
-1.5V     -213.6mA   -211.3mA   -218.6mA
-1.221V   -126.2mA   -132.6mA   -120.5mA
-1.066V   -80.29mA   -90.85mA   -69.73mA
-973mV    -55.38mA   -67.32mA   -45.06mA
-911mV    -41.77mA   -52.96mA   -36.7mA
-849mV    -33.26mA   -40.67mA   -33.31mA
-756mV    -28.21mA   -29.37mA   -29.32mA
-632mV    -23.73mA   -23.99mA   -24.36mA
-415mV    -17.36mA   -18.03mA   -17.47mA
701mV     -718.2uA   -167.7uA   -1.484mA
825mV     0A         0A         0A
1.5V      0A         0A         0A
[POWER_clamp]
|Voltage   I(typ)   I(min)   I(max)
-1.5V     257mA      263mA      253.6mA
-1.228V   145.5mA    159mA      133mA
-1.073V   85.93mA    102.7mA    69.44mA
-1.011V   64.18mA    81.49mA    48.09mA
-980mV    54.24mA    71.4mA     39.83mA
-918mV    37.81mA    52.79mA    31.15mA
-856mV    28.78mA    37.65mA    28.12mA
-794mV    25.34mA    28.18mA    25.79mA
-732mV    23.23mA    23.97mA    23.58mA
-577mV    18.83mA    19.46mA    18.64mA
725mV     426.2uA    0A         767.9uA
1.5V      0A         0A         0A
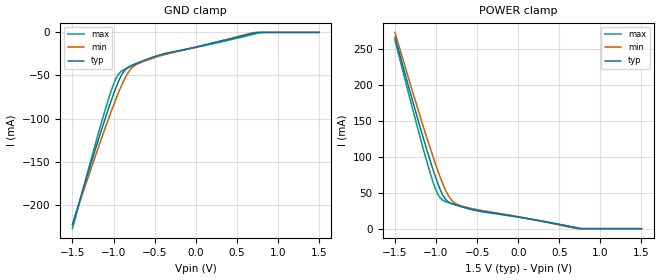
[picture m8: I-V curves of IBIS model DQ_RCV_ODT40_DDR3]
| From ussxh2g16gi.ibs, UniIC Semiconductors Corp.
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|   Model DQ_RCV_ODT40_DDR3
[Model] DQ_RCV_ODT40_DDR3
Model_type Input
Vinl =  0.615V
Vinh =  0.885V
C_comp   0.966pF   0.965pF   0.967pF
[Model Spec]
Vinh   0.885V   0.847V   0.922V
Vinl   0.615V   0.577V   0.652V
[Temperature Range]   25.000   95.000   -40.000
[Voltage Range]   1.500V   1.425V   1.575V
[GND_clamp]
|Voltage   I(typ)   I(min)   I(max)
-1.5V     -223.3mA   -222.7mA   -227.9mA
-1.221V   -135.7mA   -143.6mA   -129.6mA
-1.066V   -89.68mA   -101.5mA   -78.73mA
-973mV    -64.69mA   -77.83mA   -54.02mA
-911mV    -51.03mA   -63.34mA   -45.65mA
-849mV    -42.46mA   -50.92mA   -42.23mA
-756mV    -37.3mA    -39.39mA   -38.2mA
-663mV    -33.76mA   -34.78mA   -34.38mA
-415mV    -25.64mA   -26.75mA   -25.78mA
701mV     -1.089mA   -264.2uA   -2.245mA
825mV     0A         0A         0A
1.5V      0A         0A         0A
[POWER_clamp]
|Voltage   I(typ)   I(min)   I(max)
-1.5V     266.1mA    272.8mA    262.2mA
-1.228V   154.6mA    168.8mA    141.5mA
-1.073V   94.97mA    112.4mA    77.9mA
-1.011V   73.19mA    91.19mA    56.55mA
-980mV    63.23mA    81.08mA    48.3mA
-918mV    46.77mA    62.4mA     39.62mA
-856mV    37.69mA    47.17mA    36.58mA
-794mV    34.18mA    37.6mA     34.24mA
-732mV    31.99mA    33.26mA    31.99mA
-577mV    27.3mA     28.33mA    26.86mA
725mV     626.6uA    0A         1.132mA
1.5V      0A         0A         0A
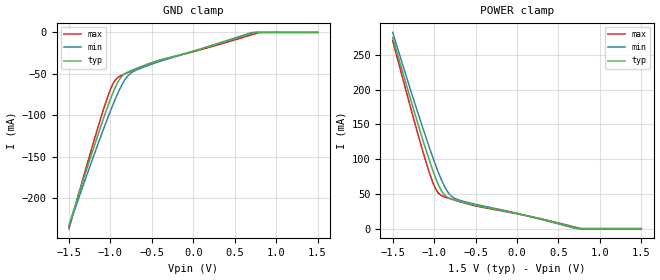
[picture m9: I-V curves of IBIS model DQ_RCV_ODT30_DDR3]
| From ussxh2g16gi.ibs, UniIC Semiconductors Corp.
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|   Model DQ_RCV_ODT30_DDR3
[Model] DQ_RCV_ODT30_DDR3
Model_type Input
Vinl =  0.615V
Vinh =  0.885V
C_comp   0.966pF   0.965pF   0.967pF
[Model Spec]
Vinh   0.885V   0.847V   0.922V
Vinl   0.615V   0.577V   0.652V
[Temperature Range]   25.000   95.000   -40.000
[Voltage Range]   1.500V   1.425V   1.575V
[GND_clamp]
|Voltage   I(typ)   I(min)   I(max)
-1.5V     -233mA     -234.1mA   -237mA
-1.221V   -145.1mA   -154.5mA   -138.6mA
-1.066V   -99.03mA   -112.2mA   -87.62mA
-973mV    -73.97mA   -88.29mA   -62.88mA
-911mV    -60.25mA   -73.68mA   -54.48mA
-818mV    -49.33mA   -56.09mA   -49.67mA
-756mV    -46.36mA   -49.36mA   -46.99mA
-694mV    -43.88mA   -45.82mA   -44.38mA
-415mV    -33.89mA   -35.43mA   -34.02mA
701mV     -1.444mA   -345.1uA   -2.979mA
825mV     0A         0A         0A
1.5V      0A         0A         0A
[POWER_clamp]
|Voltage   I(typ)   I(min)   I(max)
-1.5V     275.1mA    282.5mA    270.6mA
-1.228V   163.7mA    178.5mA    149.9mA
-1.073V   104mA      122.1mA    86.29mA
-1.011V   82.16mA    100.9mA    64.95mA
-980mV    72.19mA    90.72mA    56.69mA
-918mV    55.68mA    71.97mA    48.01mA
-856mV    46.55mA    56.66mA    44.97mA
-794mV    42.99mA    46.98mA    42.62mA
-732mV    40.72mA    42.52mA    40.34mA
-577mV    35.74mA    37.18mA    35.03mA
725mV     840.7uA    0A         1.516mA
1.5V      0A         0A         0A
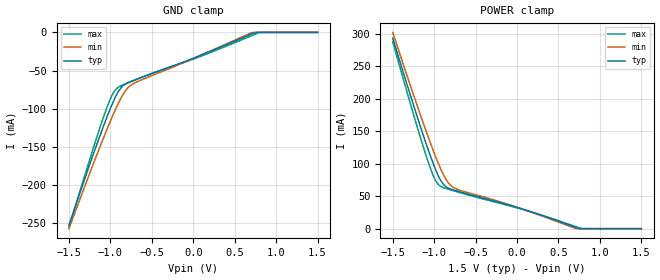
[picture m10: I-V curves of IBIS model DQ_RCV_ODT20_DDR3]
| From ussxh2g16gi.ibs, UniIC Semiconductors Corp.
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|   Model DQ_RCV_ODT20_DDR3
[Model] DQ_RCV_ODT20_DDR3
Model_type Input
Vinl =  0.615V
Vinh =  0.885V
C_comp   0.966pF   0.965pF   0.967pF
[Model Spec]
Vinh   0.885V   0.847V   0.922V
Vinl   0.615V   0.577V   0.652V
[Temperature Range]   25.000   95.000   -40.000
[Voltage Range]   1.500V   1.425V   1.575V
[GND_clamp]
|Voltage   I(typ)   I(min)   I(max)
-1.5V     -252.3mA   -256.8mA   -255.3mA
-1.221V   -164mA     -176.3mA   -156.5mA
-1.066V   -117.7mA   -133.4mA   -105.4mA
-973mV    -92.5mA    -109.2mA   -80.64mA
-911mV    -78.68mA   -94.32mA   -72.2mA
-880mV    -73.54mA   -87.56mA   -70.26mA
-818mV    -67.57mA   -76.32mA   -67.32mA
-725mV    -63.1mA    -67.11mA   -63.25mA
19mV      -33.06mA   -33.19mA   -34.13mA
701mV     -2.159mA   -514.5uA   -4.458mA
825mV     0A         0A         0A
1.5V      0A         0A         0A
[POWER_clamp]
|Voltage   I(typ)   I(min)   I(max)
-1.5V     293.2mA    302mA      287.7mA
-1.228V   181.8mA    198.1mA    166.7mA
-1.073V   122mA      141.6mA    103.1mA
-980mV    90.12mA    110mA      73.54mA
-918mV    73.53mA    91.13mA    64.86mA
-887mV    67.91mA    82.82mA    63.12mA
-825mV    62.12mA    69.91mA    60.6mA
-732mV    58.2mA     61.06mA    57.08mA
43mV      30.98mA    31.1mA     30.46mA
694mV     2.693mA    925.4uA    3.668mA
787mV     0A         0A         0A
1.5V      0A         0A         0A
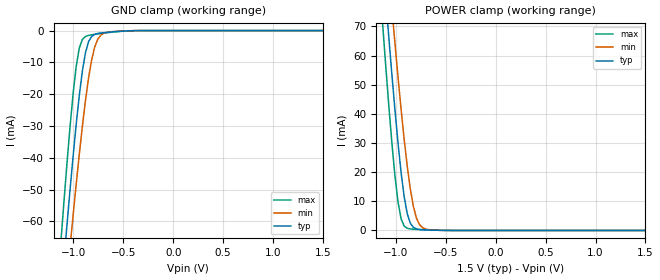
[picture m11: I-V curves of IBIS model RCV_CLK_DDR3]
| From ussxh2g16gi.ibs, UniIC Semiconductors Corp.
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|   Model RCV_CLK_DDR3
[Model] RCV_CLK_DDR3
Model_type Input
Vinl =  0.615V
Vinh =  0.885V
C_comp   0.694pF   0.694pF   0.694pF
[Model Spec]
Vinh   0.885V   0.847V   0.922V
Vinl   0.615V   0.577V   0.652V
[Temperature Range]   25.000   95.000   -40.000
[Voltage Range]   1.500V   1.425V   1.575V
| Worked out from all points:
|   GND clamp passes 1 mA (typ) near -0.77 V on its own axis
|   POWER clamp passes 1 mA (typ) near -0.82 V on its own axis
[GND_clamp]
|Voltage   I(typ)   I(min)   I(max)
-1.5V     -234.6mA   -235.5mA   -234.8mA
-1.128V   -84.6mA    -99.98mA   -67.29mA
-1.097V   -72.87mA   -89.24mA   -54.44mA
-1.066V   -61.4mA    -78.68mA   -42.08mA
-1.035V   -50.26mA   -68.31mA   -30.45mA
-1.004V   -39.59mA   -58.18mA   -19.95mA
-973mV    -29.55mA   -48.37mA   -11.32mA
-942mV    -20.46mA   -38.97mA   -5.525mA
-880mV    -6.991mA   -22.01mA   -1.848mA
-787mV    -1.189mA   -5.118mA   -1.176mA
-694mV    -640.4uA   -822.3uA   -787.7uA
1.5V      0A         0A         0A
[POWER_clamp]
|Voltage   I(typ)   I(min)   I(max)
-1.5V     266.1mA    275.5mA    256.6mA
-1.135V   93.86mA    114.7mA    71.47mA
-1.073V   66.81mA    89.05mA    43.3mA
-1.042V   53.89mA    76.58mA    30.42mA
-1.011V   41.58mA    64.45mA    18.97mA
-980mV    30.14mA    52.76mA    9.829mA
-949mV    19.95mA    41.64mA    4.036mA
-887mV    5.734mA    22mA       743.9uA
-825mV    1.051mA    8.134mA    425uA
-794mV    524.9uA    4.165mA    366.2uA
-701mV    192.7uA    446.9uA    227uA
1.5V      0A         0A         0A
